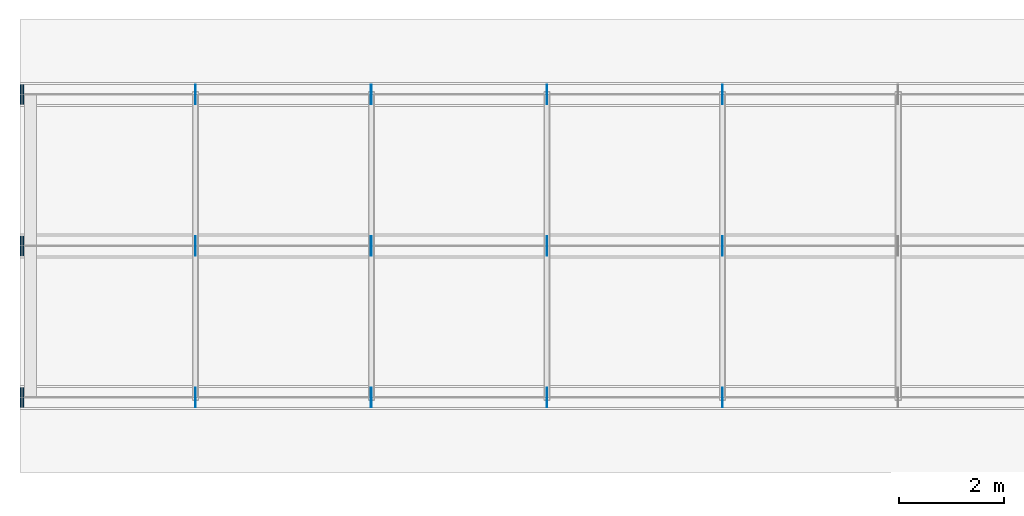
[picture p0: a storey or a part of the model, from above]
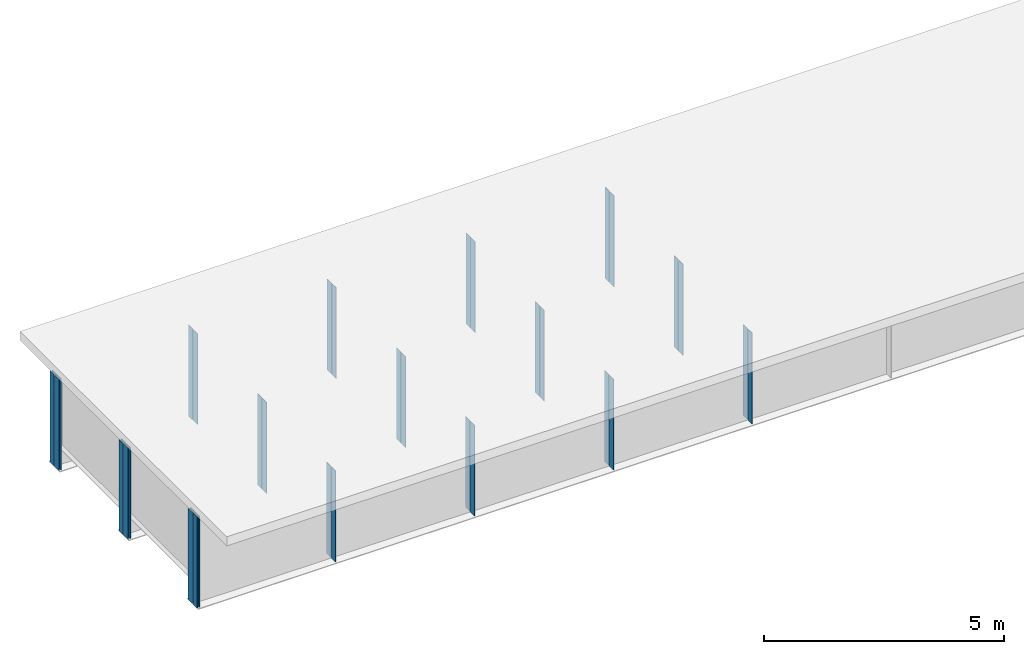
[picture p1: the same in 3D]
Properties of the parts of a building model (IFC4)

# File
Description: ViewDefinition [CoordinationView]
Time: 2026-06-10T16:00:22
Written by: IfcOpenShell 0.8.0
Made in: IfcOpenShell 0.8.0

# IfcMember (92)
In: Superstructure
Pset_OsdagBridgeProperties - Material: E250
Name | ProfileDepth_or_LegHeight | ProfileWidth_or_LegWidth | ConnectionType
4 x End Diaphragm | 1.848 | 0.225 | Pset_OsdagBridgeProperties - WebThickness: 0.02; FlangeThickness: 0.012
44 x Diagonal Brace | 0.173 | 0.115 | LONGER_LEG | Pset_OsdagBridgeProperties - ComponentRole: Intermediate Bracing Diagonal; BracingPattern: X; ProfileType: ANGLE; ProfileThickness: 0.008; StructuralSystem: Intermediate Bracing
22 x Bottom Chord |  |  | LONGER_LEG
22 x Top Chord |  |  | LONGER_LEG

# IfcPlate (99)
In: Superstructure
Pset_OsdagBridgeProperties - Material: E250
Name | ComponentRole | Thickness | Spacing
Girder Web 1 | Girder Web | 0.02 | Pset_OsdagBridgeProperties - SpanLength: 40; GirderSpacing: 2.875; Depth: 2.31
Top Flange 1 | Main Girder | Pset_OsdagBridgeProperties - SpanLength: 40; GirderSpacing: 2.875
Bottom Flange 1 | Main Girder | Pset_OsdagBridgeProperties - SpanLength: 40; GirderSpacing: 2.875
Girder Web 2 | Girder Web | 0.02 | Pset_OsdagBridgeProperties - SpanLength: 40; GirderSpacing: 2.875; Depth: 2.31
Top Flange 2 | Main Girder | Pset_OsdagBridgeProperties - SpanLength: 40; GirderSpacing: 2.875
Bottom Flange 2 | Main Girder | Pset_OsdagBridgeProperties - SpanLength: 40; GirderSpacing: 2.875
Girder Web 3 | Girder Web | 0.02 | Pset_OsdagBridgeProperties - SpanLength: 40; GirderSpacing: 2.875; Depth: 2.31
Top Flange 3 | Main Girder | Pset_OsdagBridgeProperties - SpanLength: 40; GirderSpacing: 2.875
Bottom Flange 3 | Main Girder | Pset_OsdagBridgeProperties - SpanLength: 40; GirderSpacing: 2.875
22 x Intermediate Stiffener 1 | Intermediate Stiffener | 0.012 | 3.333
8 x End Stiffener 1 | End Stiffener | 0.02
22 x Intermediate Stiffener 2 | Intermediate Stiffener | 0.012 | 3.333
8 x End Stiffener 2 | End Stiffener | 0.02
22 x Intermediate Stiffener 3 | Intermediate Stiffener | 0.012 | 3.333
8 x End Stiffener 3 | End Stiffener | 0.02

# IfcSlab, Deck Slab
In: Superstructure
Pset_OsdagBridgeProperties - ComponentRole: Deck Slab; DeckThickness: 0.23; CarriagewayWidth: 7.5; SpanLength: 40; SkewAngle: 0; Material: M30; fck_MPa: 30; fctm_MPa: 2.5; Ecm_GPa: 31
